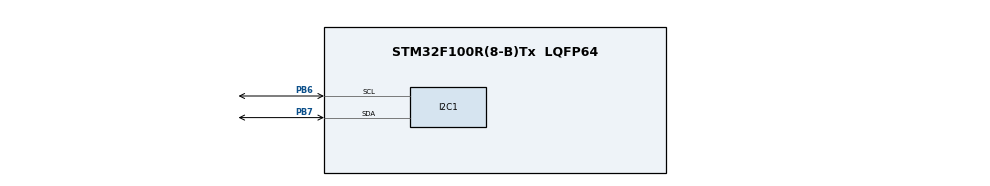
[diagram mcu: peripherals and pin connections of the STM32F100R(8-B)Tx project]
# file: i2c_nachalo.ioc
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Mcu.Family=STM32F1
Mcu.Name=STM32F100R(8-B)Tx
Mcu.Package=LQFP64
NVIC.I2C1_ER_IRQn=true\:2\:0\:true
NVIC.I2C1_EV_IRQn=true\:1\:0\:true
NVIC.PriorityGroup=NVIC_PRIORITYGROUP_4
PA13.Mode=Serial_Wire
PA13.Signal=SYS_JTMS-SWDIO
PA14.Mode=Serial_Wire
PA14.Signal=SYS_JTCK-SWCLK
PB6.Mode=I2C
PB6.Signal=I2C1_SCL
PB7.Mode=I2C
PB7.Signal=I2C1_SDA
PD0-OSC_IN.Mode=HSE-External-Oscillator
PD0-OSC_IN.Signal=RCC_OSC_IN
PD1-OSC_OUT.Mode=HSE-External-Oscillator
PD1-OSC_OUT.Signal=RCC_OSC_OUT
ProjectManager.TargetToolchain=MDK-ARM V5
RCC.AHBFreq_Value=24000000
RCC.APB1Freq_Value=24000000
RCC.APB1TimFreq_Value=24000000
RCC.APB2Freq_Value=24000000
RCC.APB2TimFreq_Value=24000000
RCC.HCLKFreq_Value=24000000
RCC.PLLMUL=RCC_PLL_MUL3
RCC.PLLSource=RCC_PLLSOURCE_HSE
RCC.SYSCLKFreq_VALUE=24000000
RCC.SYSCLKSource=RCC_SYSCLKSOURCE_PLLCLK
board=i2c_nachalo

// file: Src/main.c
/**
  ******************************************************************************
  * File Name          : main.c
  * Description        : Main program body
  ******************************************************************************
  *
  * COPYRIGHT(c) 2016 STMicroelectronics
  *
  * Redistribution and use in source and binary forms, with or without modification,
  * are permitted provided that the following conditions are met:
  *   1. Redistributions of source code must retain the above copyright notice,
  *      this list of conditions and the following disclaimer.
  *   2. Redistributions in binary form must reproduce the above copyright notice,
  *      this list of conditions and the following disclaimer in the documentation
  *      and/or other materials provided with the distribution.
  *   3. Neither the name of STMicroelectronics nor the names of its contributors
  *      may be used to endorse or promote products derived from this software
  *      without specific prior written permission.
  *
  * THIS SOFTWARE IS PROVIDED BY THE COPYRIGHT HOLDERS AND CONTRIBUTORS "AS IS"
  * AND ANY EXPRESS OR IMPLIED WARRANTIES, INCLUDING, BUT NOT LIMITED TO, THE
  * IMPLIED WARRANTIES OF MERCHANTABILITY AND FITNESS FOR A PARTICULAR PURPOSE ARE
  * DISCLAIMED. IN NO EVENT SHALL THE COPYRIGHT HOLDER OR CONTRIBUTORS BE LIABLE
  * FOR ANY DIRECT, INDIRECT, INCIDENTAL, SPECIAL, EXEMPLARY, OR CONSEQUENTIAL
  * DAMAGES (INCLUDING, BUT NOT LIMITED TO, PROCUREMENT OF SUBSTITUTE GOODS OR
  * SERVICES; LOSS OF USE, DATA, OR PROFITS; OR BUSINESS INTERRUPTION) HOWEVER
  * CAUSED AND ON ANY THEORY OF LIABILITY, WHETHER IN CONTRACT, STRICT LIABILITY,
  * OR TORT (INCLUDING NEGLIGENCE OR OTHERWISE) ARISING IN ANY WAY OUT OF THE USE
  * OF THIS SOFTWARE, EVEN IF ADVISED OF THE POSSIBILITY OF SUCH DAMAGE.
  *
  ******************************************************************************
  */
#include "stm32f1xx_hal.h"
#include "i2c.h"
#include "gpio.h"

/* USER CODE BEGIN Includes */
extern uint8_t I2C_buf[];
/* USER CODE END Includes */

/* USER CODE BEGIN PV */

uint16_t hTxNumData = 0, hRxNumData = 0;
uint8_t bTransferRequest = 0;
#define MASTER_REQ_READ    0x12
#define MASTER_REQ_WRITE   0x34

#define COUNTOF(__BUFFER__)   (sizeof(__BUFFER__) / sizeof(*(__BUFFER__)))
/* Buffer used for transmission */
uint8_t aTxBuffer[] = " ****I2C_TwoBoards communication based on IT****  ****I2C_TwoBoards communication based on IT****  ****I2C_TwoBoards communication based on IT**** ";
/* Size of Transmission buffer */
#define TXBUFFERSIZE                      (COUNTOF(aTxBuffer) - 1)
/* Size of Reception buffer */
#define RXBUFFERSIZE                      TXBUFFERSIZE
/* Buffer used for reception */
uint8_t aRxBuffer[RXBUFFERSIZE];

void SystemClock_Config(void);

/* USER CODE BEGIN PFP */
/* Private function prototypes -----------------------------------------------*/

/* USER CODE END PFP */

int main(void)
{

  /* MCU Configuration----------------------------------------------------------*/

  /* Reset of all peripherals, Initializes the Flash interface and the Systick. */
  HAL_Init();

  /* Configure the system clock */
  SystemClock_Config();

  /* Initialize all configured peripherals */
  MX_GPIO_Init();
  MX_I2C1_Init();

  /* Infinite loop */
  /* USER CODE BEGIN WHILE */
  while (1)
  {

    /* Initialize number of data variables */
    hTxNumData = 0;
    hRxNumData = 0;

		    /*##-2- Slave receive request from master ################################*/
    while(HAL_I2C_Slave_Receive_IT(&hi2c1, (uint8_t*)&bTransferRequest, 1)!= HAL_OK)
    {
    }

    while (HAL_I2C_GetState(&hi2c1) != HAL_I2C_STATE_READY)
    {
    }

		  /* If master request write operation #####################################*/
    if (bTransferRequest == MASTER_REQ_WRITE)
    {
      /*##-3- Slave receive number of data to be read ########################*/
      while(HAL_I2C_Slave_Receive_IT(&hi2c1, (uint8_t*)&hRxNumData, 2)!= HAL_OK);

      while (HAL_I2C_GetState(&hi2c1) != HAL_I2C_STATE_READY)
      {
      }

		 /*##-4- Slave receives aRxBuffer from master ###########################*/
      while(HAL_I2C_Slave_Receive_IT(&hi2c1, (uint8_t*)aRxBuffer, hRxNumData)!= HAL_OK);

      while (HAL_I2C_GetState(&hi2c1) != HAL_I2C_STATE_READY)
      {
      }
		}
		else
    {
      /*##-3- Slave receive number of data to be written #####################*/
      while(HAL_I2C_Slave_Receive_IT(&hi2c1, (uint8_t*)&hTxNumData, 2)!= HAL_OK);

      while (HAL_I2C_GetState(&hi2c1) != HAL_I2C_STATE_READY)
      {
      }

      /*##-4- Slave transmit aTxBuffer to master #############################*/
      while(HAL_I2C_Slave_Transmit_IT(&hi2c1, (uint8_t*)aTxBuffer, RXBUFFERSIZE)!= HAL_OK);

      while (HAL_I2C_GetState(&hi2c1) != HAL_I2C_STATE_READY)
      {
      }
    }

  /* USER CODE END WHILE */

  }

}

/** System Clock Configuration
*/
void SystemClock_Config(void)
{

  RCC_OscInitTypeDef RCC_OscInitStruct;
  RCC_ClkInitTypeDef RCC_ClkInitStruct;

  RCC_OscInitStruct.OscillatorType = RCC_OSCILLATORTYPE_HSE;
  RCC_OscInitStruct.HSEState = RCC_HSE_ON;
  RCC_OscInitStruct.HSEPredivValue = RCC_HSE_PREDIV_DIV2;
  RCC_OscInitStruct.PLL.PLLState = RCC_PLL_ON;
  RCC_OscInitStruct.PLL.PLLSource = RCC_PLLSOURCE_HSE;
  RCC_OscInitStruct.PLL.PLLMUL = RCC_PLL_MUL2;
  HAL_RCC_OscConfig(&RCC_OscInitStruct);

  RCC_ClkInitStruct.ClockType = RCC_CLOCKTYPE_SYSCLK;
  RCC_ClkInitStruct.SYSCLKSource = RCC_SYSCLKSOURCE_PLLCLK;
  RCC_ClkInitStruct.AHBCLKDivider = RCC_SYSCLK_DIV1;
  RCC_ClkInitStruct.APB1CLKDivider = RCC_HCLK_DIV1;
  RCC_ClkInitStruct.APB2CLKDivider = RCC_HCLK_DIV1;
  HAL_RCC_ClockConfig(&RCC_ClkInitStruct, FLASH_LATENCY_0);

  HAL_SYSTICK_Config(HAL_RCC_GetHCLKFreq()/1000);

  HAL_SYSTICK_CLKSourceConfig(SYSTICK_CLKSOURCE_HCLK);

}

/************************ (C) COPYRIGHT STMicroelectronics *****END OF FILE****/
